VERSION 5.7 ;
  NOWIREEXTENSIONATPIN ON ;
  DIVIDERCHAR "/" ;
  BUSBITCHARS "[]" ;
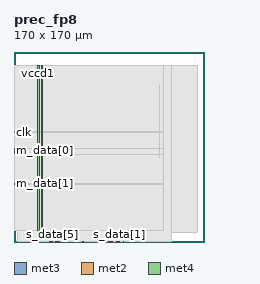
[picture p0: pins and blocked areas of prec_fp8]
MACRO prec_fp8
  CLASS BLOCK ;
  FOREIGN prec_fp8 ;
  ORIGIN 0.000 0.000 ;
  SIZE 170.000 BY 170.000 ;
  PIN clk
    DIRECTION INPUT ;
    USE SIGNAL ;
    ANTENNAGATEAREA 1.286700 ;
    ANTENNADIFFAREA 0.434700 ;
    PORT
      LAYER met3 ;
        RECT 0.000 97.960 0.600 98.560 ;
    END
  END clk
  PIN m_data[0]
    DIRECTION OUTPUT ;
    USE SIGNAL ;
    ANTENNADIFFAREA 0.795200 ;
    PORT
      LAYER met3 ;
        RECT 0.000 81.640 0.600 82.240 ;
    END
  END m_data[0]
  PIN m_data[1]
    DIRECTION OUTPUT ;
    USE SIGNAL ;
    ANTENNADIFFAREA 0.795200 ;
    PORT
      LAYER met3 ;
        RECT 0.000 51.720 0.600 52.320 ;
    END
  END m_data[1]
  PIN m_data[2]
    DIRECTION OUTPUT ;
    USE SIGNAL ;
    ANTENNADIFFAREA 0.795200 ;
    PORT
      LAYER met3 ;
        RECT 0.000 80.280 0.600 80.880 ;
    END
  END m_data[2]
  PIN m_data[3]
    DIRECTION OUTPUT ;
    USE SIGNAL ;
    ANTENNADIFFAREA 0.795200 ;
    PORT
      LAYER met2 ;
        RECT 81.970 0.000 82.250 0.280 ;
    END
  END m_data[3]
  PIN m_data[4]
    DIRECTION OUTPUT ;
    USE SIGNAL ;
    ANTENNADIFFAREA 0.795200 ;
    PORT
      LAYER met2 ;
        RECT 86.570 0.000 86.850 0.280 ;
    END
  END m_data[4]
  PIN m_data[5]
    DIRECTION OUTPUT ;
    USE SIGNAL ;
    ANTENNADIFFAREA 0.795200 ;
    PORT
      LAYER met2 ;
        RECT 85.650 0.000 85.930 0.280 ;
    END
  END m_data[5]
  PIN m_data[6]
    DIRECTION OUTPUT ;
    USE SIGNAL ;
    ANTENNADIFFAREA 0.795200 ;
    PORT
      LAYER met2 ;
        RECT 84.730 0.000 85.010 0.280 ;
    END
  END m_data[6]
  PIN m_data[7]
    DIRECTION OUTPUT ;
    USE SIGNAL ;
    ANTENNADIFFAREA 0.795200 ;
    PORT
      LAYER met3 ;
        RECT 0.000 83.000 0.600 83.600 ;
    END
  END m_data[7]
  PIN m_last
    DIRECTION OUTPUT ;
    USE SIGNAL ;
    ANTENNADIFFAREA 0.795200 ;
    PORT
      LAYER met3 ;
        RECT 0.000 78.920 0.600 79.520 ;
    END
  END m_last
  PIN m_ready
    DIRECTION INPUT ;
    USE SIGNAL ;
    ANTENNAGATEAREA 0.647700 ;
    ANTENNADIFFAREA 0.434700 ;
    PORT
      LAYER met2 ;
        RECT 40.570 0.000 40.850 0.280 ;
    END
  END m_ready
  PIN m_valid
    DIRECTION OUTPUT ;
    USE SIGNAL ;
    ANTENNADIFFAREA 0.795200 ;
    PORT
      LAYER met2 ;
        RECT 61.730 0.000 62.010 0.280 ;
    END
  END m_valid
  PIN rst
    DIRECTION INPUT ;
    USE SIGNAL ;
    ANTENNAGATEAREA 0.647700 ;
    ANTENNADIFFAREA 0.434700 ;
    PORT
      LAYER met2 ;
        RECT 36.890 0.000 37.170 0.280 ;
    END
  END rst
  PIN s_data[0]
    DIRECTION INPUT ;
    USE SIGNAL ;
    ANTENNAGATEAREA 0.647700 ;
    ANTENNADIFFAREA 0.434700 ;
    PORT
      LAYER met2 ;
        RECT 87.490 0.000 87.770 0.280 ;
    END
  END s_data[0]
  PIN s_data[1]
    DIRECTION INPUT ;
    USE SIGNAL ;
    ANTENNAGATEAREA 0.647700 ;
    ANTENNADIFFAREA 0.434700 ;
    PORT
      LAYER met2 ;
        RECT 93.930 0.000 94.210 0.280 ;
    END
  END s_data[1]
  PIN s_data[2]
    DIRECTION INPUT ;
    USE SIGNAL ;
    ANTENNAGATEAREA 0.647700 ;
    ANTENNADIFFAREA 0.434700 ;
    PORT
      LAYER met2 ;
        RECT 97.610 0.000 97.890 0.280 ;
    END
  END s_data[2]
  PIN s_data[3]
    DIRECTION INPUT ;
    USE SIGNAL ;
    ANTENNAGATEAREA 0.647700 ;
    ANTENNADIFFAREA 0.434700 ;
    PORT
      LAYER met2 ;
        RECT 92.090 0.000 92.370 0.280 ;
    END
  END s_data[3]
  PIN s_data[4]
    DIRECTION INPUT ;
    USE SIGNAL ;
    ANTENNAGATEAREA 0.647700 ;
    ANTENNADIFFAREA 0.434700 ;
    PORT
      LAYER met2 ;
        RECT 32.290 0.000 32.570 0.280 ;
    END
  END s_data[4]
  PIN s_data[5]
    DIRECTION INPUT ;
    USE SIGNAL ;
    ANTENNAGATEAREA 0.647700 ;
    ANTENNADIFFAREA 0.434700 ;
    PORT
      LAYER met2 ;
        RECT 34.130 0.000 34.410 0.280 ;
    END
  END s_data[5]
  PIN s_data[6]
    DIRECTION INPUT ;
    USE SIGNAL ;
    ANTENNAGATEAREA 0.647700 ;
    ANTENNADIFFAREA 0.434700 ;
    PORT
      LAYER met2 ;
        RECT 31.370 0.000 31.650 0.280 ;
    END
  END s_data[6]
  PIN s_data[7]
    DIRECTION INPUT ;
    USE SIGNAL ;
    ANTENNAGATEAREA 0.647700 ;
    ANTENNADIFFAREA 0.434700 ;
    PORT
      LAYER met2 ;
        RECT 33.210 0.000 33.490 0.280 ;
    END
  END s_data[7]
  PIN s_last
    DIRECTION INPUT ;
    USE SIGNAL ;
    ANTENNAGATEAREA 0.647700 ;
    ANTENNADIFFAREA 0.434700 ;
    PORT
      LAYER met2 ;
        RECT 38.730 0.000 39.010 0.280 ;
    END
  END s_last
  PIN s_ready
    DIRECTION OUTPUT ;
    USE SIGNAL ;
    ANTENNADIFFAREA 0.795200 ;
    PORT
      LAYER met2 ;
        RECT 37.810 0.000 38.090 0.280 ;
    END
  END s_ready
  PIN s_valid
    DIRECTION INPUT ;
    USE SIGNAL ;
    ANTENNAGATEAREA 0.647700 ;
    ANTENNADIFFAREA 0.434700 ;
    PORT
      LAYER met2 ;
        RECT 39.650 0.000 39.930 0.280 ;
    END
  END s_valid
  PIN vccd1
    DIRECTION INOUT ;
    USE POWER ;
    PORT
      LAYER met4 ;
        RECT 21.040 10.640 22.640 158.000 ;
    END
  END vccd1
  PIN vssd1
    DIRECTION INOUT ;
    USE GROUND ;
    PORT
      LAYER met4 ;
        RECT 24.340 10.640 25.940 158.000 ;
    END
  END vssd1
  OBS
      LAYER nwell ;
        RECT 5.330 10.795 164.410 157.845 ;
      LAYER li1 ;
        RECT 5.520 10.795 164.220 157.845 ;
      LAYER met1 ;
        RECT 3.290 8.540 164.220 158.000 ;
      LAYER met2 ;
        RECT 3.310 0.560 141.120 157.945 ;
        RECT 3.310 0.280 31.090 0.560 ;
        RECT 31.930 0.280 32.010 0.560 ;
        RECT 32.850 0.280 32.930 0.560 ;
        RECT 33.770 0.280 33.850 0.560 ;
        RECT 34.690 0.280 36.610 0.560 ;
        RECT 37.450 0.280 37.530 0.560 ;
        RECT 38.370 0.280 38.450 0.560 ;
        RECT 39.290 0.280 39.370 0.560 ;
        RECT 40.210 0.280 40.290 0.560 ;
        RECT 41.130 0.280 61.450 0.560 ;
        RECT 62.290 0.280 81.690 0.560 ;
        RECT 82.530 0.280 84.450 0.560 ;
        RECT 85.290 0.280 85.370 0.560 ;
        RECT 86.210 0.280 86.290 0.560 ;
        RECT 87.130 0.280 87.210 0.560 ;
        RECT 88.050 0.280 91.810 0.560 ;
        RECT 92.650 0.280 93.650 0.560 ;
        RECT 94.490 0.280 97.330 0.560 ;
        RECT 98.170 0.280 141.120 0.560 ;
      LAYER met3 ;
        RECT 0.600 98.960 133.335 157.925 ;
        RECT 1.000 97.560 133.335 98.960 ;
        RECT 0.600 84.000 133.335 97.560 ;
        RECT 1.000 78.520 133.335 84.000 ;
        RECT 0.600 52.720 133.335 78.520 ;
        RECT 1.000 51.320 133.335 52.720 ;
        RECT 0.600 10.715 133.335 51.320 ;
      LAYER met4 ;
        RECT 130.015 75.655 130.345 139.905 ;
  END
END prec_fp8
END LIBRARY

